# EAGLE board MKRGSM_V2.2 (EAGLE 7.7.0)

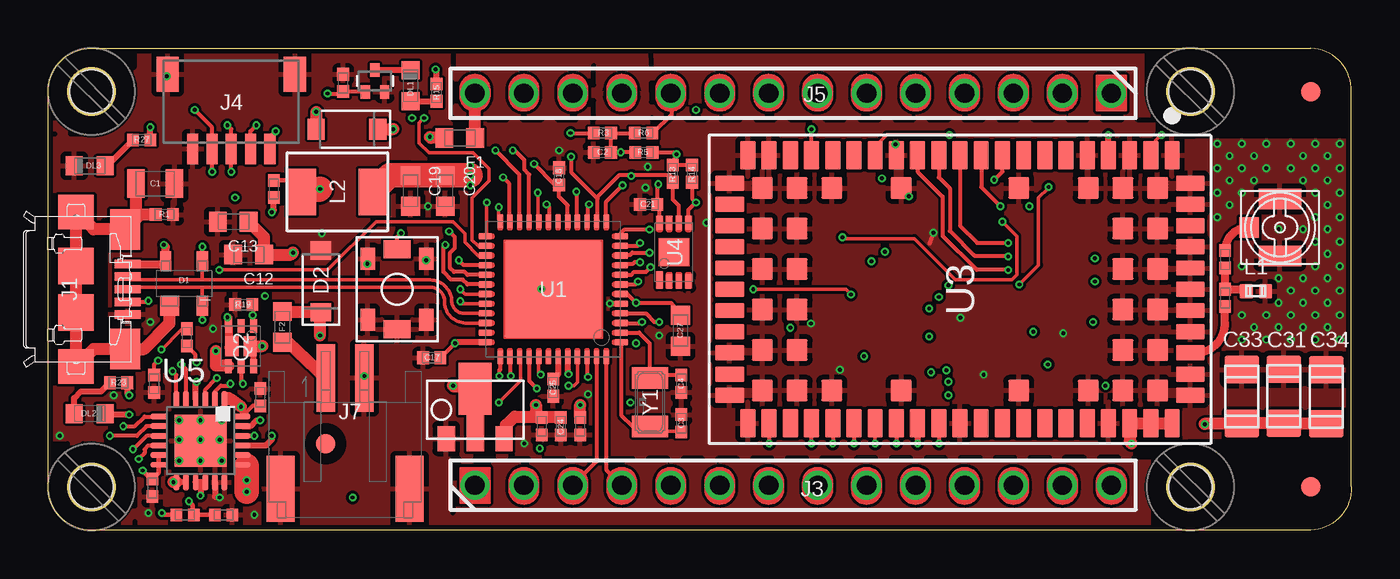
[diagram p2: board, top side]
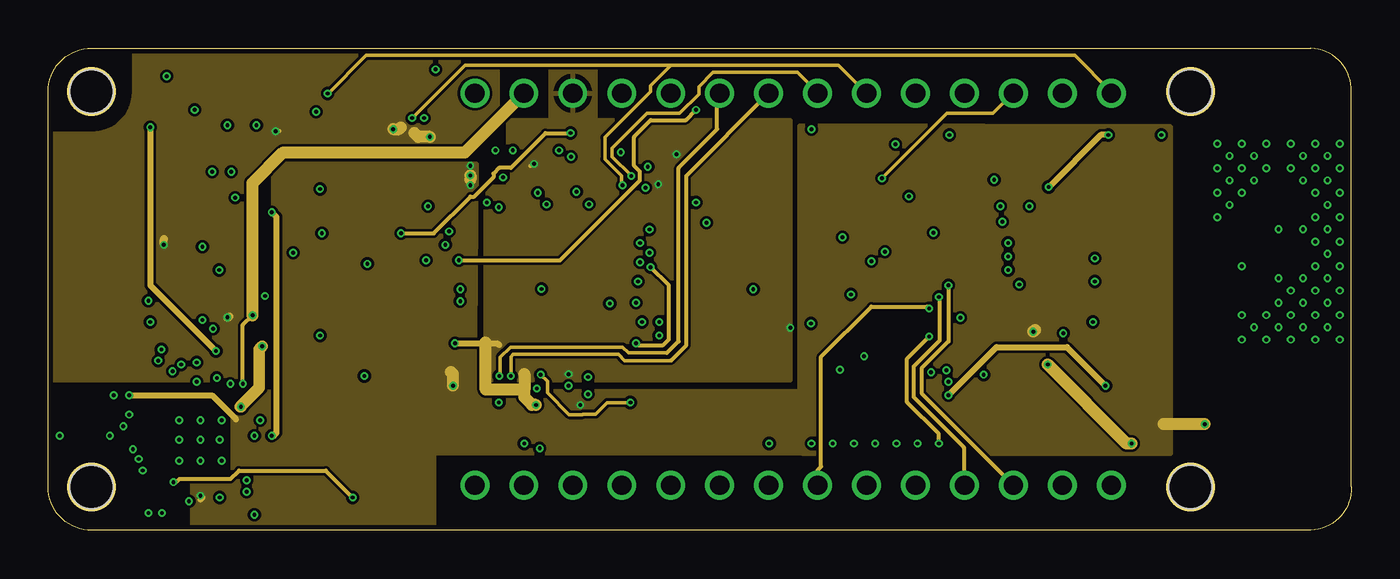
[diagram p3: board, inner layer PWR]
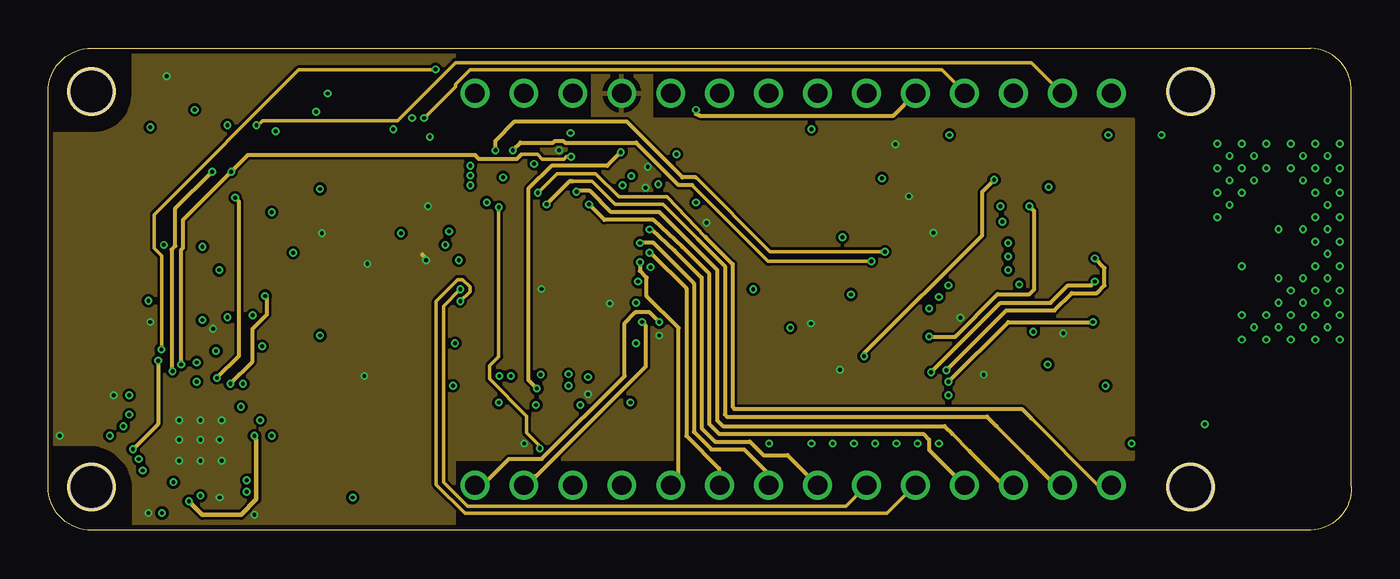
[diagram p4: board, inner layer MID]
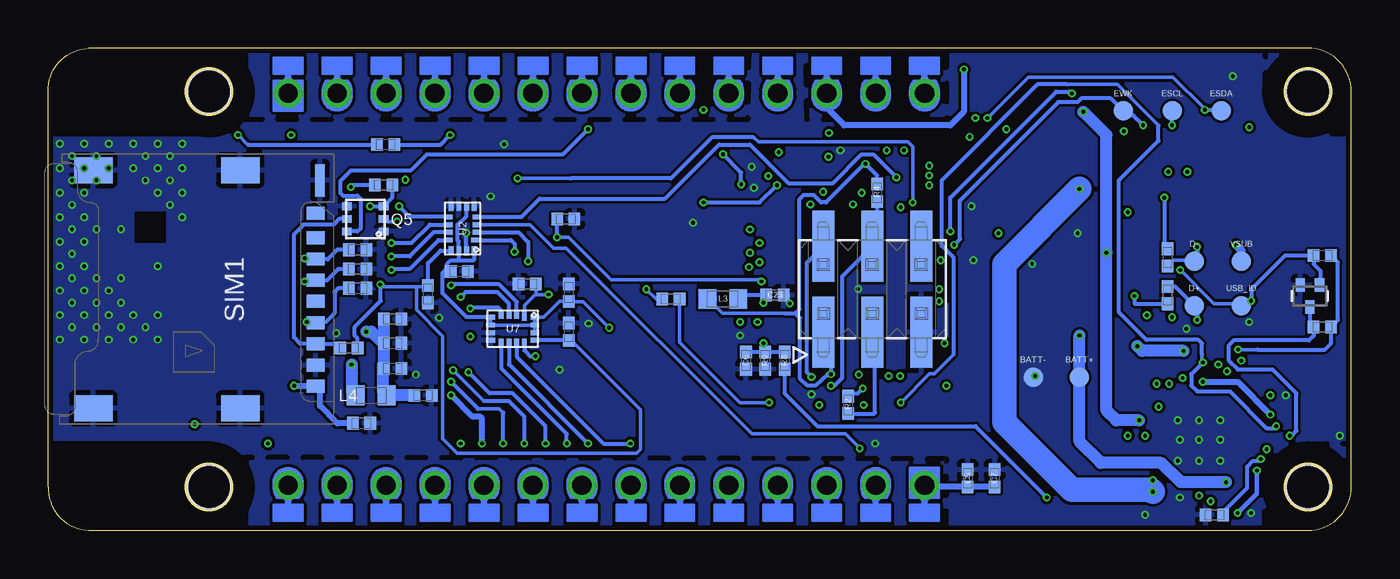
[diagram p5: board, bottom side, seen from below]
Size 67.6 x 25 mm. Coordinates in mm from the lower left corner, seen from the top.
Outline: 0,2.25 0,22.75 arc-90 2.25,25 65.5,25 arc-90 67.6,22.75 67.6,2.25 arc-90 65.5,0 2.25,0 arc-90 0,2.25
Copper layers (1*2*15*16): Top 0.035mm / dielectric 0.2mm / PWR 0.0175mm / dielectric 0.3mm / MID 0.0175mm / dielectric 0.2mm / Bottom 0.035mm
Design rules "B&B_4layers *": minimum track width 6mil, minimum drill 0.195mm, track to track 5.5mil, track to pad 5.5mil, pad to pad 5mil, via to via 5mil, smd to smd 0mil, copper to edge 10mil, drill to drill 8mil, minimum pad ring 6mil, minimum via ring 4mil, stop-mask expansion 4mil, vias tented up to drill 25mil, thermal gap 10mil
Net classes: 0 default: width 0.19 mm, drill 0.19 mm; 1 usb: width 0.19 mm, drill 0.19 mm, clearance 0.127 mm
Holes 2.25 mm at 2.25,2.25 59.25,2.25 59.25,22.75 2.25,22.75
tRestrict: area 0,0 to 4.5,4.5; area 0,20.5 to 4.5,25; area 57,20.5 to 61.5,25; area 57,0 to 61.5,4.5; 115 lines
bRestrict: area 0,0 to 4.5,4.5; area 0,20.5 to 4.5,25; area 57,0 to 61.5,4.5; area 57,20.5 to 61.5,25; 119 lines

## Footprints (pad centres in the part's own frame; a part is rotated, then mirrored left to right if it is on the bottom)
TP-1.00MM = smd 1 x 1 bottom: X 0,0
0805-R2013X50N@1 = smd 0.95 x 1.45: 1 -1,0; 2 1,0
0402-1005X55N = smd 0.62 x 0.62: 1 -0.45,0; 2 0.45,0
0603-1608X90N = smd 0.95 x 1: 1 -0.8,0; 2 0.8,0
C1206 = smd 1.8 x 1.45: 1 0,1.4; 2 0,-1.4
SOT190P230X110-4N = smd 1 x 1: 1 -1.15,0.75 | smd 1 x 0.6: 2 -1.15,-0.95; 3 1.15,-0.95; 4 1.15,0.95
SODFL3517X110N = smd 0.91 x 1.07: A 1.605,0; C -1.605,0
LEDC1608X80N-AK = smd 0.9 x 0.95: A 0.8,0; C -0.8,0
FD-1-1.5 = smd 1.016 x 1.016: P$1 0,0
ZX62-AB-5PA = smd 0.4 x 1.35: 1 -1.3,3.025; 2 -0.65,3.025; 3 0,3.025; 4 0.65,3.025; 5 1.3,3.025 | smd 2.1 x 1.6: 6 3.1,2.9; 11 -3.1,2.9 | smd 1.8 x 1.9: 7 4,0.35; 10 -4,0.35 | smd 1.9 x 1.9: 8 1.2,0.35; 9 -1.2,0.35
2X3_SMT = smd 1.143 x 3.683: 1 -2.54,-2.223; 2 -2.54,2.223; 3 0,-2.223; 4 0,2.223; 5 2.54,-2.223; 6 2.54,2.223
1X14_SMD_TH = drill 1: 1 0,0; 2 2.54,0; 3 5.08,0; 4 7.62,0; 5 10.16,0; 6 12.7,0; 7 15.24,0; 8 17.78,0; 9 20.32,0; 10 22.86,0; 11 25.4,0; 12 27.94,0; 13 30.48,0; 14 33.02,0
SM05B-SRSS-TB = smd 0.6 x 1.55: 1 -2,2.425; 2 -1,2.425; 3 0,2.425; 4 1,2.425; 5 2,2.425 | smd 1.2 x 1.8: SH1 -3.3,-1.45; SH2 3.3,-1.45
U.FL-R-SMT-1(60) = smd 1.05 x 2.2: GND1 -1.475,0; GND2 1.475,0 | smd 1.05 x 1: SIG 0,-1.6
JST-S2B-PH-SM4-TB = smd 1 x 3.5: 1 -1,2.95; 2 1,2.95 | smd 1.5 x 3.4: 3 3.35,-2.8; 4 -3.35,-2.8
C0402 = smd 0.75 x 0.7: 1 0,0.5; 2 0,-0.5
SRP4020 = smd 1.5 x 2.4: 1 -1.85,0; 2 1.85,0
C&K_PTS820_NO_HOLES = smd 1.15 x 0.75: 1 -1.575,1.525; 2 -1.575,-1.525; 3 1.575,1.525; 4 1.575,-1.525 | smd 0.95 x 1.4: 5 -2.075,0; 6 2.075,0
SOTFL50P160X78-3 = smd 0.5 x 0.66: D 0,0.57; G -0.5,-0.57; S 0.5,-0.57
SON65P205X205X75-8N-MWSD = smd 0.67 x 0.37: A 1.04,-0.65; D 1.04,0.65; G -1.04,0; K -1.04,-0.65; NC 1.04,0; S -1.04,0.65 | smd 1 x 0.7: D2 0,0.467; K2 0,-0.467
PWR_SC70-6L2 = smd 0.4 x 0.5: 1 -0.65,-0.95; 2 0,-0.95; 3 0.65,-0.95; 4 0.65,0.95; 5 0,0.95; 6 -0.65,0.95
MICROSIM8 = smd 0.67 x 0.95: CLK -0.47,6.77; GND 3.93,6.77; IO -1.57,6.77; NC1 -2.67,6.77; NC2 -3.94,6.77; RST 1.73,6.77; SW 2.83,6.77; VCC 5.03,6.77; VPP 0.63,6.77 | smd 1.7 x 0.5: SH1 -5.64,6.995 | smd 1.35 x 2: SH2 -6.175,2.865; SH3 6.175,2.865; SH4 -6.175,-4.755; SH5 6.175,-4.755
QFN50P700X700X90-49XN-EPSQ515 = smd 0.65 x 0.28: 1 -3.525,2.75; 2 -3.525,2.25; 3 -3.525,1.75; 4 -3.525,1.25; 5 -3.525,0.75; 6 -3.525,0.25; 7 -3.525,-0.25; 8 -3.525,-0.75; 9 -3.525,-1.25; 10 -3.525,-1.75; 11 -3.525,-2.25; 12 -3.525,-2.75; 25 3.525,-2.75; 26 3.525,-2.25; 27 3.525,-1.75; 28 3.525,-1.25; 29 3.525,-0.75; 30 3.525,-0.25; 31 3.525,0.25; 32 3.525,0.75; 33 3.525,1.25; 34 3.525,1.75; 35 3.525,2.25; 36 3.525,2.75 | smd 0.28 x 0.65: 13 -2.75,-3.525; 14 -2.25,-3.525; 15 -1.75,-3.525; 16 -1.25,-3.525; 17 -0.75,-3.525; 18 -0.25,-3.525; 19 0.25,-3.525; 20 0.75,-3.525; 21 1.25,-3.525; 22 1.75,-3.525; 23 2.25,-3.525; 24 2.75,-3.525; 37 2.75,3.525; 38 2.25,3.525; 39 1.75,3.525; 40 1.25,3.525; 41 0.75,3.525; 42 0.25,3.525; 43 -0.25,3.525; 44 -0.75,3.525; 45 -1.25,3.525; 46 -1.75,3.525; 47 -2.25,3.525; 48 -2.75,3.525 | smd 5 x 5: 49 0,0
RSV = smd 0.25 x 0.55: 1 -0.6,-0.7 | smd 0.25 x 0.45: 2 -0.2,-0.75; 3 0.2,-0.75; 4 0.6,-0.75; 9 0.6,0.75; 10 0.2,0.75; 11 -0.2,0.75; 12 -0.6,0.75 | smd 0.45 x 0.25: 5 1.15,-0.6; 6 1.15,-0.2; 7 1.15,0.2; 8 1.15,0.6; 13 -1.15,0.6; 14 -1.15,0.2; 15 -1.15,-0.2; 16 -1.15,-0.6
SARA-96 = smd 1.5 x 0.8: 1 -6.95,11; 2 -6.95,9.9; 3 -6.95,8.8; 4 -6.95,7.7; 5 -6.95,6.6; 6 -6.95,5.5; 7 -6.95,4.4; 8 -6.95,3.3; 9 -6.95,2.2; 10 -6.95,1.1; 11 -6.95,0; 12 -6.95,-1.1; 13 -6.95,-2.2; 14 -6.95,-3.3; 15 -6.95,-4.4; 16 -6.95,-5.5; 17 -6.95,-6.6; 18 -6.95,-7.7; 19 -6.95,-8.8; 20 -6.95,-9.9; 21 -6.95,-11; 33 6.95,-11; 34 6.95,-9.9; 35 6.95,-8.8; 36 6.95,-7.7; 37 6.95,-6.6; 38 6.95,-5.5; 39 6.95,-4.4; 40 6.95,-3.3; 41 6.95,-2.2; 42 6.95,-1.1; 43 6.95,0; 44 6.95,1.1; 45 6.95,2.2; 46 6.95,3.3; 47 6.95,4.4; 48 6.95,5.5; 49 6.95,6.6; 50 6.95,7.7; 51 6.95,8.8; 52 6.95,9.9; 53 6.95,11 | smd 0.8 x 1.5: 22 -5.5,-11.95; 23 -4.4,-11.95; 24 -3.3,-11.95; 25 -2.2,-11.95; 26 -1.1,-11.95; 27 0,-11.95; 28 1.1,-11.95; 29 2.2,-11.95; 30 3.3,-11.95; 31 4.4,-11.95; 32 5.5,-11.95; 54 5.5,11.95; 55 4.4,11.95; 56 3.3,11.95; 57 2.2,11.95; 58 1.1,11.95; 59 0,11.95; 60 -1.1,11.95; 61 -2.2,11.95; 62 -3.3,11.95; 63 -4.4,11.95; 64 -5.5,11.95 | smd 1.1 x 1.1: 65 -5.25,10.25; 66 -3.15,10.25; 67 -1.05,10.25; 68 1.05,10.25; 69 3.15,10.25; 70 5.25,10.25; 71 -5.25,8.45; 72 -3.15,8.45; 73 -1.05,8.45; 74 1.05,8.45; 75 3.15,8.45; 76 5.25,8.45; 77 -5.25,6.65; 78 5.25,6.65; 79 -5.25,3.05; 80 5.25,3.05; 81 -5.25,-3.05; 82 5.25,-3.05; 83 -5.25,-6.65; 84 5.25,-6.65; 85 -5.25,-8.45; 86 -3.15,-8.45; 87 -1.05,-8.45; 88 1.05,-8.45; 89 3.15,-8.45; 90 5.25,-8.45; 91 -5.25,-10.25; 92 -3.15,-10.25; 93 -1.05,-10.25; 94 1.05,-10.25; 95 3.15,-10.25; 96 5.25,-10.25
SON50P300X200X60-9N-EP160X140 = smd 0.85 x 0.3: 1 -1.45,0.75 | smd 0.7 x 0.3: 2 -1.525,0.25; 3 -1.525,-0.25; 4 -1.525,-0.75; 5 1.525,-0.75; 6 1.525,-0.25; 7 1.525,0.25; 8 1.525,0.75 | smd 1.4 x 1.6: 9 0,0
QFN24 = smd 0.3 x 0.85: 1 1.25,2.155; 2 0.75,2.155; 3 0.25,2.155; 4 -0.25,2.155; 5 -0.75,2.155; 6 -1.25,2.155; 13 -1.25,-2.155; 14 -0.75,-2.155; 15 -0.25,-2.155; 16 0.25,-2.155; 17 0.75,-2.155; 18 1.25,-2.155 | smd 0.85 x 0.3: 7 -2.155,1.25; 8 -2.155,0.75; 9 -2.155,0.25; 10 -2.155,-0.25; 11 -2.155,-0.75; 12 -2.155,-1.25; 19 2.155,-1.25; 20 2.155,-0.75; 21 2.155,-0.25; 22 2.155,0.25; 23 2.155,0.75; 24 2.155,1.25 | smd 2.7 x 2.7: 25 0,0
SOT89-3L = smd 0.9 x 1.3: 1 -1.5,0; 3 1.5,0 | smd 0.9 x 1.9: 2 0,0.3 | smd 1.7 x 2.7: TH 0,2.6
ABS07 = smd 1.1 x 1.9: 1 -1.25,0; 2 1.25,0

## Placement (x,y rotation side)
BATT+  DNP  [TP-1.00MM]  14.1,7.95 0 top
BATT-  DNP  [TP-1.00MM]  16.5,7.95 0 top
C1  4n7  [0805-R2013X50N@1]  5.55,17.98 0 top
C2  100n  [0402-1005X55N]  28.75,19.6 180 top
C3  20p  [0402-1005X55N]  32.85,5.55 270 top
C4  20p  [0402-1005X55N]  32.85,7.6 90 top
C5  4u7  [0402-1005X55N]  19.9,2.7 90 bottom
C6  100n  [0402-1005X55N]  31.4,8.8 270 bottom
C7  100n  [0402-1005X55N]  18.5,2.7 90 bottom
C8  100n  [0402-1005X55N]  46.27,13.43 180 bottom
C9  100n  [0402-1005X55N]  47.9,12.25 270 bottom
C10  15p  [0402-1005X55N]  61.05,12.05 90 top
C11  33p  [0402-1005X55N]  61.05,14.05 90 top
C12  10u  [0603-1608X90N]  10.4,14.3 180 top
C13  10u  [0603-1608X90N]  9.6,16 180 top
C14  1u  [0402-1005X55N]  11,6.9 90 top
C15  47n  [0402-1005X55N]  11.7,17.7 90 top
C16  4u7  [0402-1005X55N]  9.1,0.8 0 top
C17  100n  [0402-1005X55N]  19.9,8.95 180 top
C18  100n  [0402-1005X55N]  26.5,18.35 90 top
C19  10u  [0603-1608X90N]  18.8,17.6 270 top
C20  10u  [0603-1608X90N]  20.6,17.6 270 top
C21  100n  [0402-1005X55N]  31.15,16.9 180 top
C22  1u  [0402-1005X55N]  27.6,5.4 270 top
C23  100n  [0402-1005X55N]  29.9,12.2 0 bottom
C24  100n  [0402-1005X55N]  26.6,5.4 270 top
C25  1u  [0402-1005X55N]  26.2,7.4 270 top
C26  1u  [0402-1005X55N]  25.6,5.4 270 top
C27  4u7  [0603-1608X90N]  32.8,10.35 270 top
C28  10n  [0402-1005X55N]  48.15,7 0 bottom
C29  100n  [0402-1005X55N]  49.74,8.39 0 bottom
C30  15p  [0402-1005X55N]  49.74,9.7 0 bottom
C31  100uF  [C1206]  64.1,6.95 180 top
C32  100n  [0402-1005X55N]  51.35,5.55 180 bottom
C33  100uF  [C1206]  61.91,6.94 180 top
C34  100uF  [C1206]  66.3,6.92 180 top
C35  100n  [0402-1005X55N]  40.6,12.32 270 bottom
C36  100n  [0402-1005X55N]  40.6,10.3 90 bottom
C37  56p  [0402-1005X55N]  49.74,10.95 0 bottom
D1  PRTR5V  [SOT190P230X110-4N]  7.05,12.8 90 top
D2  PMEG6020  [SODFL3517X110N]  14.15,12.9 90 top
D3  PMEG6020  [SODFL3517X110N]  15.5,20.8 180 top
D4  PESD0402  [0402-1005X55N]  51.55,12.55 180 bottom
D5  PESD0402  [0402-1005X55N]  51.55,13.55 180 bottom
D6  PESD0402  [0402-1005X55N]  51.55,14.55 180 bottom
D+  DNP  [TP-1.00MM]  8.15,11.65 0 top
D-  DNP  [TP-1.00MM]  8.15,13.95 0 top
DL1  YELLOW  [LEDC1608X80N-AK]  18.8,23.05 270 top
DL2  ORANGE  [LEDC1608X80N-AK]  2.15,6.05 180 top
DL3  GREEN  [LEDC1608X80N-AK]  2.15,18.9 0 top
ESCL  DNP  [TP-1.00MM]  9.29,21.75 0 top
ESDA  DNP  [TP-1.00MM]  6.75,21.75 0 top
EWK  DNP  [TP-1.00MM]  11.83,21.75 0 top
F1  MFFSMF050  [0603-1608X90N]  21.35,20.35 180 top
F2  MFFSMF050  [0603-1608X90N]  12.15,10.55 90 top
FD1  DNP  [FD-1-1.5]  14.4,4.5 0 top
FD2  DNP  [FD-1-1.5]  65.5,22.75 0 top
FD3  DNP  [FD-1-1.5]  65.5,2.25 0 top
FRAME1  DNP  [FRAME]  not placed on the board
FRAME2  DNP  [FRAME-NO-BAN]  not placed on the board
J1  -  [ZX62-AB-5PA]  1.1,12.5 270 top
J2  DNP  [2X3_SMT]  24.85,12.5 0 bottom
J3  -  [1X14_SMD_TH]  22.13,2.34 0 top
J4  -  [SM05B-SRSS-TB]  9.5,22.2 180 top
J5  -  [1X14_SMD_TH]  55.15,22.66 180 top
J6  -  [U.FL-R-SMT-1(60)]  63.9,15.7 270 top
J7  -  [JST-S2B-PH-SM4-TB]  15.4,4.95 0 top
L1  39nH  [C0402]  62.65,12.4 270 top
L2  2u2  [SRP4020]  15,17.55 0 top
L3  BLM18PG471  [0603-1608X90N]  32.6,12 0 bottom
L4  BLM18EG221  [0603-1608X90N]  50.85,7 180 bottom
PB1  PTS820  [C&K_PTS820_NO_HOLES]  18.1,12.5 90 top
Q1  2N7002  [SOTFL50P160X78-3]  16.95,23.3 0 top
Q2  SIA817  [SON65P205X205X75-8N-MWSD]  10,9.55 90 top
Q3  2N7002  [SOTFL50P160X78-3]  2.15,12.15 180 bottom
Q5  2N7002DW-7-FNO_PAD  [PWR_SC70-6L2]  51.15,16.15 90 bottom
R1  1M  [0402-1005X55N]  6.03,16.38 180 top
R2  39R  [0402-1005X55N]  26.1,6.5 90 bottom
R3  330R  [0402-1005X55N]  28.75,20.6 0 top
R4  1k  [0402-1005X55N]  24.6,17.5 90 bottom
R5  10k  [0402-1005X55N]  30.9,19.6 0 top
R6  330R  [0402-1005X55N]  30.89,20.6 0 top
R7  DNP  [0402-1005X55N]  9.53,12.2 270 bottom
R8  330k  [0402-1005X55N]  29.4,8.8 270 bottom
R9  1M2  [0402-1005X55N]  30.4,8.8 90 bottom
R10  100k  [0402-1005X55N]  40.75,16.15 180 bottom
R11  0R  [0402-1005X55N]  35.3,12 0 bottom
R12  100k  [0402-1005X55N]  50.1,20 180 bottom
R13  4k7  [0402-1005X55N]  32.4,18.5 90 top
R14  4k7  [0402-1005X55N]  33.4,18.5 90 top
R15  330R  [0402-1005X55N]  20.15,22.7 270 top
R16  100k  [0402-1005X55N]  15.3,23.2 270 top
R17  DNP  [0402-1005X55N]  9.53,14.15 90 bottom
R18  DNP  [0402-1005X55N]  42.75,12.78 0 bottom
R19  100k  [0402-1005X55N]  10.15,11.7 0 top
R21  10k  [0402-1005X55N]  1.5,14.25 180 bottom
R23  330R  [0402-1005X55N]  3.65,7.65 0 top
R24  10k  [0402-1005X55N]  7.2,10 270 top
R25  10k  [0402-1005X55N]  5.5,7.6 90 top
R26  10k  [0402-1005X55N]  1.5,10.55 180 bottom
R27  390R  [0402-1005X55N]  4.85,20.25 0 top
R28  330R  [0402-1005X55N]  7.1,0.8 180 bottom
R29  10k  [0402-1005X55N]  5.4,2.2 90 top
R30  5k49  [0402-1005X55N]  7.1,0.8 180 top
R31  10k  [0402-1005X55N]  52,9.45 0 bottom
R32  1k  [0402-1005X55N]  50.2,17.9 180 bottom
SIM1  -  [MICROSIM8]  60.5,12.5 270 bottom
U1  D21G18  [QFN50P700X700X90-49XN-EPSQ515]  26.2,12.5 180 top
U2  SN74AVC4T774  [RSV]  46.1,15.65 90 bottom
U3  SARA-U201  [SARA-96]  47.3,12.5 270 top
U4  ECC508  [SON50P300X200X60-9N-EP160X140]  32.46,14.43 90 top
U5  BQ24195L  [QFN24]  7.9,4.65 0 top
U6  AP721533  [SOT89-3L]  22.15,4.75 0 top
U7  SN74AVC4T774  [RSV]  43.5,10.45 180 bottom
U$5  [MH_RND_F_2.2MM_NM]  2.25,2.25 90 top
U$6  [MH_RND_F_2.2MM_NM]  2.25,22.75 90 top
U$7  [MH_RND_F_2.2MM_NM]  59.25,22.75 90 top
U$8  [MH_RND_F_2.2MM_NM]  59.25,2.25 90 top
USB_ID  DNP  [TP-1.00MM]  5.7,11.65 0 top
VSUB  DNP  [TP-1.00MM]  5.7,13.95 0 top
Y1  32768Hz  [ABS07]  31.23,6.64 270 top

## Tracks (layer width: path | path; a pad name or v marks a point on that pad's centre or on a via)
+1V8  (via drill 0.2)
  Top 0.19: v50.38,12.75 51.38,13.75 51.38,17.25 51.88,17.75 v51.9,17.8
  Top 0.305: U3.4 v55,20.5
  PWR 0.305: v55,20.5 54.6,20.5 v51.9,17.8
  Bottom 0.19: 48.5,12.62 48.5,11.43 47.15,10.07 47.15,4.75 46.4,4 37.08,4 36.88,4.2 36.88,6.25 40.38,9.75 C36.1 | 48.5,12.62 48,12.62 C9.1 | v50.38,12.75 50.25,12.62 48.5,12.62
  Bottom 0.2: C36.1 U7.13 | C9.1 47.9,13.85 47.25,14.5 U2.13 | R32.2 51.8,17.9 v51.9,17.8 | R31.2 51.55,9.95 51.7,10.1 51.7,10.55 50.35,11.9 50.35,12.72 v50.38,12.75
+3V3  (via drill 0.2)
  Top 0.19: v5.88,9.38 6.88,10.38 7.12,10.38 R24.1
  Top 0.2: R14.2 R13.2 v32.6,19.5 32.5,19.6 R5.2 | U4.8 31.71,16.74 C21.1 31.6,17.9 v31.65,17.95 | U1.17 26.95,16.85 26.5,17.3 C18.1 26.3,17.9 v25.2,19 | C17.1 v21.1,9.7
  Top 0.305: U1.44 26.95,8.15 v27,8.1 | U1.36 21.15,9.75 v21.1,9.7 | R15.1 20.15,23.85 v20.1,23.9
  Top 0.61: U6.3 23.75,5.45 24.2,5.9 25.1,5.9 | 25.1,5.9 25.55,5.9 C26.1 C24.1 | v25.3,6.5 25.3,6.1 25.1,5.9
  PWR 0.2: v25.2,19 25.1,19 25,18.9
  PWR 0.305: v21.1,9.7 23.3,9.7 23.4,9.6
  PWR 0.61: v25.3,6.5 25.1,6.5 24.7,6.9 24.7,7.3 | 24.7,8.1 24.7,7.3 | 24.7,7.3 22.7,7.3 22.7,9.62 U1.36
  MID 0.19: v5.88,9.38 5.88,14.25 5.5,14.62 5.5,16.38 13,23.88 20,23.88 v20.1,23.9
  Bottom 0.19: v5.88,9.38 4.88,9.38 | 29.38,11.25 32.62,11.25 33.38,12 L3.1 | 25.25,19 v25.2,19 | 32.62,19.5 v32.6,19.5 | U7.6 44.62,10.62 42.38,10.62 U7.15 | v38.5,10.5 39.85,11.85 40.38,11.85 C35.2 41.08,11.88 41.9,11.05 42.3,11.05
  Bottom 0.2: 25.25,19 27.25,17 27.5,17 27.9,17.4 28.4,17.4 28.62,17.18 28.62,11.47 28.85,11.25 | v31.65,17.95 31.65,18.55 v32.6,19.5 | 29.38,11.25 28.85,11.25 | 28.85,11.25 28.6,11 28.6,7.85 28.2,7.5 27.8,7.5 27.15,8.1 v27,8.1 27,9.89 | R26.1 1.05,10.75 | R21.1 0.7,13.9 0.7,10.9 R26.1 | 4.88,9.38 1.38,9.38 1.05,9.7 R26.1 | U7.14 U7.15 U7.16 42.3,11.05 | U7.6 U7.5 45.9,11.05 47.15,12.3 47.15,13.35 46.9,13.6 | 46.9,13.6 C8.2 | 45.88,16.77 U2.6 45.9,16.27 46.38,15.85 46.38,15.05 46.3,14.97 U2.14 46.3,14.05 46.25,14 | R4.2 24.6,18.4 v25.2,19 | U2.16 45.5,14.05 45.55,14 46.25,14 | 46.9,13.6 46.9,13.82 46.73,14 46.25,14
  Bottom 0.305: 27,9.89 J2.1 | v20.1,23.9 20.1,21.7 20.8,21 26.3,21 27.2,21.9 27.2,22.64 J5.12
  pour PWR: 26.05,25 26.05,21.25 23.85,21.25 23.85,17.85 23.8,17.8 22.7,17.8 22.7,7.8 38.5,7.8 38.5,21.25 28.4,21.25 28.4,24.95
+3V8  (via drill 0.2)
  Top 0.305: U5.15 U5.16 8.1,2.5 7.9,2.3 v7.9,1.8 | R23.2 4.1,7.1 v4.2,7
  Top 0.61: C34.1 64.12,5.53 C31.1 61.92,5.55 C33.1 60.04,5.54 v60,5.5 | U6.2 U6.TH 21.05,7.45 v21,7.5 | C22.1 v27.6,6.5
  Top 1.27: L2.2 17.7,18.4 C19.1 C20.1 v21.9,18.4
  PWR 0.305: v7.9,1.8 7.9,1.6 8,1.7 | v4.2,7 8.5,7 9.75,5.75
  PWR 0.61: v60,5.5 57.85,5.5 | 51.2,10.4 v51.1,10.3 | v21.9,18.4 21.9,18.2 | v21,7.5 21,8.1 20.9,8.2
  Bottom 0.61: C28.1 L4.1 50.25,7.2 50.25,8.57 C29.1 C30.1 | v51.1,10.3 50.84,10.3 C30.1 | C37.1 C30.1
  other vias: 21.9,18.9 21.9,17.9
  pour PWR: 9.6,7.2 11.7,7.2 11.7,19 22.2,19 22.1,7.2 39,7.2 39,21 58.2,20.95 58.2,3.95 20,4 20,0 7.5,0 7.5,2.9 9.6,2.9
+5V  (via drill 0.2)
  Top 0.2: J4.1 11.5,20.4 v11.8,20.7
  Top 0.406: J1.1 5.95,13.8 D1.4 6.1,14.7 v6,14.8 | Q2.D2 9.35,9.48 Q2.D 9.35,11 v9.3,11.05
  Top 0.61: F1.2 19.85,20.35 v19.8,20.4 | D3.C v17.9,20.8
  PWR 0.2: v11.8,20.7 12,20.7
  PWR 0.406: v6,14.8 6,15.1 | v9.3,11.05 9.3,11 9.4,11.1
  PWR 0.61: v19.8,20.4 19.2,20.4 19,20.6 | v17.9,20.8 18.2,20.8 18.3,20.9
  Bottom 0.406: VSUB.X 5.7,14.5 v6,14.8
  pour PWR: 23.3,25 4.45,25 4.45,22.7 arc-90 2.3,20.55 0,20.55 0,7.8 11.2,7.8 11.2,19.5 23.3,19.5
GND  (via drill 0.2)
  Top 0.19: 55.62,7.5 U3.76 | 55.5,9 55.62,9
  Top 0.2: PB1.4 19.62,14.03 v19.6,14 | v45.92,15.43 45.73,14.88
  Top 0.305: U5.17 8.65,1.75 v8.9,1.7
  MID 0.2: v19.6,14 19.6,14.1 19.4,14.3
  Bottom 0.2: C23.2 29.45,12.08 v29.14,11.77 | 45.9,15.4 v45.92,15.43 45.92,14.57 45.9,14.57 U2.15
  other vias: 31.7,10.1 6.8,5.7 7.9,5.7 9,5.7 9,3.6 7.9,3.6 6.8,3.6 6.8,4.7 7.9,4.7 8.9,4.7 5.3,10.8 5.2,0.9 10.7,0.8 24.7,4.5 28,7.05 26.5,19.7 8.55,10.45 3.4,7 67,20.05 65.73,20.05 64.46,20.05 61.92,20.05 63.19,20.05 60.65,20.05 60.65,18.78 60.65,17.51 60.65,16.24 61.92,17.51 61.92,18.78 63.19,18.78 64.46,18.78 65.73,18.78 67,18.78 67,17.51 65.73,17.51 67,16.24 67,14.97 67,13.7 67,12.43 67,11.16 65.73,11.16 64.46,11.16 61.92,11.16 63.19,11.16 61.92,9.89 63.19,9.89 64.46,9.89 65.73,9.89 67,9.89 65.73,12.43 64.46,12.43 65.73,13.7 65.73,14.97 65.73,16.24 61.92,13.7 62.55,10.53 63.83,10.53 65.09,10.53 66.36,10.53 66.36,11.79 65.09,11.79 63.83,11.79 66.36,13.06 65.09,13.06 66.36,14.34 66.36,15.61 66.36,16.88 65.09,15.61 63.83,15.61 66.36,18.14 65.09,18.14 62.55,18.14 61.28,18.14 61.28,19.41 62.55,19.41 61.28,16.88 63.83,13.06 66.36,19.41 65.09,19.41 14.2,15.4 43.95,20.02 44.66,17.32 16.55,13.81 19.7,16.8 25.59,12.52 16.4,8 30.98,17.77 34.15,15.95 31.1,18.85 0.6,4.9 6.15,23.55 48.52,8.07 47.33,11.03 39.58,10.72 41.08,8.32 52.66,10.21
  pour Bottom: 0,0 0,25 67.6,25 67.6,0
  pour Top: 0,-0.1 0,24.9 28.5,25 57.3,25.1 57.3,0.1
  pour Top (isolate 0.1): 57.3,25.1 67.6,25.1 67.6,0 57.3,0
  pour MID: 0,20.55 2.4,20.55 arc90 4.45,22.6 4.45,25 21,25 21,21.3 28.3,21.3 28.3,25 31.25,25 31.25,21.3 56.25,21.3 56.25,3.7 21,3.7 21,0 4.5,0 4.5,2.1 arc90 2.1,4.5 0,4.5
MCTS  (via drill 0.2)
  Top 0.2: U3.11 47.3,15.8 48.2,14.9 v49.8,14.9
  Bottom 0.2: v49.8,14.9 48.75,14.9 47.8,15.85 U2.10
MDTR  (via drill 0.2)
  Top 0.2: v49.08,18.18 49.5,18.6 U3.9
  MID 0.2: v42.33,9.03 42.33,9.18 48.45,15.3 48.45,17.55 v49.08,18.18
  Bottom 0.2: U7.12 42.9,9.32 42.6,9.03 v42.33,9.03
MI2SCLK  (via drill 0.2)
  Top 0.2: v39.6,4.5 U3.36
  Bottom 0.19: v39.6,4.5 39.7,4.5
  Bottom 0.2: v39.6,4.5 43.7,8.6 U7.10
MI2SFS  (via drill 0.2)
  Top 0.2: U3.34 v37.4,4.5
  Bottom 0.2: v37.4,4.5 38.8,4.5 43.3,9 U7.11
MI2SRX  (via drill 0.2)
  Top 0.2: U3.37 v40.7,4.5
  Bottom 0.2: v40.7,4.5 40.7,5 44.1,8.4 U7.9
MRST  (via drill 0.2)
  Top 0.2: U3.18 v39.6,20.8
  Bottom 0.2: v39.6,20.8 40.9,19.5 47.95,19.5 48.8,18.65 51.9,18.65 52.45,18.1 52.45,17.5 52.3,17.35 51.55,17.35 51.4,17.2 51.4,15.65 51.55,15.5 Q5.6
MRTS  (via drill 0.2)
  Top 0.2: U3.10 48.4,17.8 v49.4,16.8
  Bottom 0.2: U2.9 48.85,16.25 v49.4,16.8
MRX  (via drill 0.2)
  Top 0.2: U3.13 45.1,18.6 46.4,17.3 46.4,15.28 48.17,13.5 v49.8,13.5
  Bottom 0.2: v49.8,13.5 49.73,13.57 48.83,13.57 47.35,15.05 U2.12
MTX  (via drill 0.2)
  Top 0.2: U3.12 46.2,18.3 46.77,17.73 46.77,15.53 48.05,14.25 49.75,14.25 v49.8,14.2
  Bottom 0.2: U2.11 47.6,15.45 48.85,14.2 v49.8,14.2
N17658775  (via drill 0.2)
  Top 0.2: PB1.6 18.1,15.2 v18.3,15.4 | v27.1,20.6 R3.1
  PWR 0.2: v27.1,20.6 25.8,20.6 24,18.8 23.4,18.8 23.1,18.5 23.1,18.3 22.1,17.3 21.9,17.3 20,15.4 v18.3,15.4
N17798864
  Top 0.305: DL2.A 1.35,6.85 1.7,7.2 2.75,7.2 R23.1
N17834267
  Top 0.305: DL3.A 3.05,18.9 R27.1
N17852357  (via drill 0.2)
  Top 0.2: U1.6 30.05,12.25 v30.5,11.8 32.3,11.8 C27.1
  Bottom 0.2: v30.5,11.8 30.45,12.1 C23.1 31.6,12.2 L3.2
N17852431
  Top 0.305: U1.43 26.45,8.1 C25.1
N$1
  Top 0.61: R1.2 4.78,16.38 | 4.78,16.38 J1.11 2.35,15.6 J1.10 J1.9 J1.8 J1.7 2.35,9.4 J1.6 4.97,9.4 6.3,10.72 D1.1 | C1.1 4.55,16.6 4.78,16.38
N$2
  Top 0.61: F1.1 22.15,22.64 J5.14
N$3
  Top 0.61: F2.1 12.45,9.75 J7.1
N$4
  Bottom 0.2: J2.3 24.7,10.13 24.7,6.1 24.75,6.05 R2.1
N$5
  Top 0.406: U3.56 59.5,9.2 arc90 61.05,10.75 C10.1
N$6  (via drill 0.2)
  Top 0.2: U1.8 30.25,13.25 30.4,13.4 31,13.4 v31.25,13.65
  PWR 0.2: v30.5,9.7 30.6,9.6 31.9,9.6 32.2,9.9 32.2,12.7 v31.25,13.65
  Bottom 0.2: C6.1 R9.2 | R9.2 R8.1 | R9.2 30.4,9.6 v30.5,9.7
N$7
  Top 0.305: DL1.A R15.2
N$8
  Top 0.406: J6.SIG 62.25,15.7 arc90 C11.2
N$9  (via drill 0.2)
  Top 0.19: v36.58,12.5 41.38,12.5 v41.65,12.22
  Bottom 0.19: R18.2 42.3,12.28 42.35,12.22 | 42.35,12.22 42.9,11.68 U7.1 | v41.65,12.22 42.35,12.22 | R11.1 36.08,12 v36.58,12.5
N$10
  Top 0.305: DL1.C 16.97,23.85 Q1.D
N$11  (via drill 0.2)
  Top 0.2: U3.42 v46.2,4.5
  PWR 0.2: v46.2,4.5 46.2,5 44.55,6.65 44.55,8.9 v45.7,10.05
  MID 0.2: v45.7,10.05 47.05,10.05 49.25,12.25 50.9,12.25 51.15,12.5 51.15,16.55 v50.9,16.8
  Bottom 0.2: R32.1 49.75,17.25 Q5.3 v50.9,16.8
N$12  (via drill 0.2)
  Top 0.61: U3.53 U3.52 U3.51 56.1,4.6 v56.2,4.5
  PWR 0.61: v56.2,4.5 55.95,4.5 v51.85,8.6
  Bottom 0.61: v51.85,8.6 51.85,7.2 L4.2
N$13  (via drill 0.2)
  Top 0.19: v46.75,20.5 43.5,20.5 43,20 43,19.5 U3.15
  Bottom 0.2: R12.1 47.25,20 v46.75,20.5
N$14
  Top 0.406: C11.1 C10.2 62.05,12.5 arc-90 L1.2
N$15  (via drill 0.2)
  Top 0.24: C15.2 13.15,18.15 L2.1
  Top 0.305: v10.3,2.6 10.3,3.35 10.24,3.4 U5.19 U5.20
  Top 1.27: L2.1 14.05,17.65 v14.1,17.7 | v10.3,2 10.3,3.35
  Bottom 1.27: v10.3,2 10.4,2.1 14.5,2.1 18,5.6 18,13.8 v14.1,17.7
N$16  (via drill 0.2)
  Top 0.2: U5.2 8.65,7.2 8.95,7.5 9.35,7.5 v9.45,7.6
  MID 0.2: v9.45,7.6 10.6,8.75 10.6,10.45 11.35,11.2 11.35,12.05 v11.25,12.15
  Bottom 0.2: v11.25,12.15 11.25,11.75 R7.2
N$17  (via drill 0.2)
  Top 0.19: 10.1,6.2 v10,6.4
  Top 0.2: 10.1,6.1 10.1,5.95 U5.24 10.61,6.45 C14.1 | U5.1 9.39,6.8
  Top 0.305: Q2.K 10.65,9.12 Q2.K2 | R27.2 v5.3,20.9 | 10.1,6.1 10.1,6.2
  Top 0.605: 9.39,6.8 9.49,6.8 v10,6.4
  Top 0.61: 9.35,6.85 9.39,6.8 9.4,6.8 | Q2.K2 v11.1,9.55 | v8.7,9.3 8.7,8.55 9.31,8.55 Q2.S
  PWR 0.305: v5.3,20.9 5.3,12.7 v8.7,9.3
  PWR 0.605: v10,6.4 9.95,6.4 10.95,7.4 10.95,9.4 v11.1,9.55
  Bottom 0.61: v8.7,9.3 10.85,9.3 v11.1,9.55
N$18  (via drill 0.2)
  Top 0.305: U5.21 11.3,4.4 11.6,4.7 v11.6,4.9 | v11.6,16.5 11.7,16.6 C15.1
  PWR 0.305: v11.6,4.9 11.7,4.9 11.85,5.05 11.85,16.25 v11.6,16.5
N$19  (via drill 0.2)
  Top 0.2: U5.10 5.2,4.4 5,4.2 5,4 v4.7,3.7
  Bottom 0.2: R28.1 6.65,0.95 5.4,2.2 5.4,3.3 5.1,3.6 4.8,3.6 v4.7,3.7
N$20  (via drill 0.2)
  Top 0.2: U5.3 8.15,7.3 v8.75,7.9
  MID 0.2: v8.75,7.9 9.9,9.05 9.9,17.05 v9.7,17.25
  Bottom 0.2: R17.2 9.7,14.82 v9.7,17.25
N$21  (via drill 0.2)
  Top 0.24: C16.1 R30.1 7.5,0.85 7.5,1.3 v7.3,1.5 | U5.22 v10.7,4.9
  MID 0.24: v10.7,4.9 10.7,4.8 10.8,4.7 10.8,1.6 10,0.8 8,0.8 v7.3,1.5
N$22  (via drill 0.2)
  Top 0.2: U5.8 5.1,5.4 4.6,4.9 v3.2,4.9
  Bottom 0.2: v3.2,4.9 3.1,4.9 2.85,5.15 2.85,7.1 4.1,8.35 5.9,8.35 6.35,8.8 6.35,9.6 6.1,9.85 2.2,9.85 1.95,10.1 R26.2 2.15,10.75 Q3.D
N$23  (via drill 0.2)
  Top 0.24: U5.11 U5.12 5.75,3 R29.2 5.35,2.65 v4.9,3.1 | R30.2 6,0.8 v5.9,0.9
  Bottom 0.24: v4.9,3.1 4.9,1.9 v5.9,0.9
N$24  (via drill 0.2)
  Top 0.2: R25.2 5.5,8.6 v5.7,8.8 | U5.9 5.1,4.9 v4.4,4.2
  MID 0.2: v5.7,8.8 5.7,5.5 v4.4,4.2
PA00_XIN32
  Top 0.2: U1.1 29.73,5.97 30.3,5.4 31.21,5.4 Y1.2 31.46,5.15 C3.2
PA01_XOUT32
  Top 0.2: U1.2 30.65,10.25 31.2,9.7 31.2,8.61 Y1.1 31.39,8.05 C4.2
PA02_AIN0  (via drill 0.2)
  Top 0.2: U1.3 30.75,10.75 v30.8,10.8
  MID 0.2: J3.2 25.14,2.8 25.3,2.8 31,8.5 31,10.6 v30.8,10.8
PA03_VREFA  (via drill 0.2)
  Top 0.2: U1.4 31,11.25 31.45,10.8 v31.7,10.8
  MID 0.2: v31.7,10.8 31.2,11.3 30.45,11.3 29.9,10.75 29.9,8 25.6,3.7 23.9,3.7 22.61,2.4 22.2,2.4 J3.1
  Bottom 0.305: C7.1 C5.1 22.05,2.25 J3.1
PA04_AIN4  (via drill 0.2)
  Top 0.2: v30.7,13.9 30.4,13.9 30.3,13.8 29.77,13.8 U1.9
  MID 0.2: J3.5 32.3,2.4 32.7,2.8 32.7,10.5 31.05,12.15 31.05,13.1 30.7,13.45 v30.7,13.9
PA05_AIN5  (via drill 0.2)
  Top 0.2: U1.10 29.77,14.3 30.2,14.3 30.3,14.4 v31.2,14.4
  MID 0.2: J3.6 34.8,2.38 34.8,3.2 33.1,4.9 33.1,12.55 31.3,14.35 31.3,14.4 v31.2,14.4
PA06_AIN6  (via drill 0.2)
  Top 0.2: U1.11 30.55,14.75 v30.7,14.9
  MID 0.2: v30.7,14.9 31.4,14.9 33.5,12.8 33.5,5.1 34.4,4.2 36.1,4.2 37.4,2.9 37.4,2.37 J3.7
PA07_AIN7  (via drill 0.2)
  Top 0.2: U1.12 29.73,15.43 29.9,15.6 v31.2,15.6
  PWR 0.2: J3.8 39.91,3.12 40.1,3.3 40.1,9 42.7,11.6 45.6,11.6 v45.7,11.5
  MID 0.2: v31.2,15.6 31.3,15.6 32.5,14.5 33.9,13.1 33.9,5.3 34.6,4.6 36.4,4.6 37.1,3.9 38.35,3.9 J3.8
  Bottom 0.2: 45.62,11.57 v45.7,11.5 45.65,11.55 44.25,11.55 44.1,11.4 U7.4
PA08_S0_I2C_SDA  (via drill 0.2)
  Top 0.2: U1.13 28.95,17.05 v29.8,17.9 | 33.61,16.99 v33.6,17 | v7.6,21.8 8.5,20.9 J4.4 v8.5,18.6 | U5.6 6.65,8.05 v6.45,8.25 | U4.5 33.21,16.61 v33.6,17 | R14.1 33.4,17.2 v33.6,17
  PWR 0.19: 32.26,24.06 32.33,24.12 41,24.12 42.38,22.75 J5.6 | 32.26,24.06 31.25,23.05 31.25,22.75 28.88,20.38 28.88,19.25 29.75,18.38 29.75,18 v29.8,17.9 | v18.88,21.38 21.62,24.12 32.25,24.12 32.26,24.06
  MID 0.2: v6.45,8.25 6.4,8.3 6.4,14.55 6.6,14.75 6.6,16.7 v8.5,18.6
  Bottom 0.19: v18.88,21.38 16.75,23.5 9.25,23.5 7.62,21.88 v7.6,21.8
  Bottom 0.2: v7.6,21.8 6.8,21.8 ESDA.X | v33.6,17 30.7,17 v29.8,17.9
PA09_S0_I2C_SCL  (via drill 0.2)
  Top 0.19: v30.25,18.38 30.25,18.4 | v27.12,19.38 27.12,19.25
  Top 0.2: 28.5,16.07 U1.14 28.48,16.02 28.5,16.05 28.5,17.2 28.45,17.25 | 28.45,17.25 29.6,18.4 30.25,18.4 32.25,18.4 R13.1 32.4,17.15 32.71,16.84 U4.6 | v9.3,21 9.5,20.8 J4.3 v9.5,18.6 | U5.5 7.15,8.35 v6.9,8.6 | 27.12,19.25 27.12,18.57 28.45,17.25
  PWR 0.19: v30.25,18.38 29.25,19.38 29.25,19.8 31.07,21.62 32.75,21.62 33.75,22.62 33.75,23 34.5,23.75 38.88,23.75 39.88,22.75 J5.7
  MID 0.19: v27.12,19.38 26.88,19.38 26.75,19.25 25.62,19.25 25.38,19.5 24.55,19.5
  MID 0.2: v6.9,8.6 6.9,14.55 7,14.65 7,16.1 v9.5,18.6 10.35,19.45 22.15,19.45 22.35,19.25 24.3,19.25 24.55,19.5
  Bottom 0.2: v9.3,21 ESCL.X
PA10_TCC0-W2  (via drill 0.2)
  Top 0.2: U1.15 28,16.07 28,16.85 v28.05,16.9
  PWR 0.2: J3.11 47.5,2.38 47.5,4.3 44.9,6.9 44.9,8.5 46.25,9.85 46.25,12.05 v46.2,12.1
  MID 0.2: 47.5,2.38 J3.11 45.7,4.17 45.7,4.7 45.4,5 34.8,5 34.3,5.5 34.3,13.3 32.9,14.7 31.4,16.1 28.85,16.1 v28.05,16.9
  Bottom 0.2: 46.08,12.22 v46.2,12.1 45.95,12.35 44.3,12.35 43.7,11.75 U7.3
PA11_TCC0-W3  (via drill 0.2)
  Top 0.2: v27.4,17.55 27.4,16.07 U1.16
  PWR 0.2: v46.7,12.7 46.7,9.8 45.3,8.4 45.3,7.12 J3.12
  MID 0.19: 46.9,5 47.8,4.1
  MID 0.2: J3.12 49.56,2.34 47.8,4.1 | v27.4,17.55 27.5,17.6 28.1,17.6 29.2,16.5 31.7,16.5 34.7,13.5 34.7,5.7 35,5.4 46.5,5.4 46.9,5
  Bottom 0.2: U7.2 43.3,11.85 44.2,12.75 46.65,12.75 v46.7,12.7
PA12_S2_TX  (via drill 0.2)
  Top 0.2: v24.1,19.7 24.2,19.7 24.7,19.2 24.7,18.7 24.95,18.45 U1.21
  MID 0.19: v42.7,13.95 37.35,13.95 33.4,17.9
  MID 0.2: v24.1,19.7 24.5,20.1 26.2,20.1 26.3,20.2 26.7,20.2 26.8,20.1 30.5,20.1 32.7,17.9 33.4,17.9
  Bottom 0.2: U2.2 43.2,15.45 42.7,14.95 v42.7,13.95
PA13_S2_RX  (via drill 0.2)
  Top 0.2: U1.22 24.45,18.45 v23.2,19.7
  MID 0.19: v43.4,14.45 37.45,14.45 33.6,18.3
  MID 0.2: v23.2,19.7 23.2,20.2 24.2,21.2 30,21.2 32.9,18.3 33.6,18.3
  Bottom 0.2: U2.1 43.6,15.05 43.4,14.85 v43.4,14.45
PA14_S2_RTS  (via drill 0.2)
  Top 0.2: v23.6,18.3 23.9,18 23.9,16.07 U1.23
  Bottom 0.2: v23.6,18.3 24.8,19.5 25.4,19.5 26.9,18 29.2,18 31.2,20 32.8,20 35.6,17.2 42.1,17.2 43.05,16.25 U2.4
PA15_S2_CTS  (via drill 0.2)
  Top 0.19: v23.38,16.75 23.38,16.12 U1.24
  MID 0.19: v23.38,16.75 23.38,9 22.9,8.53 22.9,7.85 24.82,5.92 24.82,5.05 25.5,4.38 v25.5,4.25
  Bottom 0.19: v25.5,4.25 26.25,5 31.1,5 40.73,14.62 41.38,14.62 42.6,15.85 U2.3
PA16_S1_MOSI  (via drill 0.2)
  Top 0.19: v22.75,17 22.75,15.25 U1.25
  PWR 0.19: v43.25,18.25 46.62,21.62 49,21.62 50,22.62 J5.3
  Bottom 0.19: 31,20.38 30.75,20.15 23,20.15 22.75,19.9 v22.75,17 | v43.25,18.25 40.5,18.25
  Bottom 0.2: 31,20.38 33.17,20.38 35.3,18.25 40.5,18.25
PA17_S1_SCK  (via drill 0.2)
  Top 0.19: U1.26 22.3,14.75 22,15.05 22,17.25 22.88,18.12 22.88,18.75 22.05,19.57 19.75,19.57 19.25,20.07 19.25,21.12 v19.5,21.38
  MID 0.19: v19.5,21.38 21.12,23 21.12,23.12 21.88,23.88 46.38,23.88 47.5,22.75 J5.4
PA18_OTG  (via drill 0.2)
  Top 0.19: U1.27 22.3,14.25 21.62,14.93 21.62,15.38 21,16 17,16 14.5,13.5 v8.88,13.5
  Top 0.2: J1.4 5.15,11.85 v5.2,11.9
  Bottom 0.19: v8.88,13.5 7.12,11.75 5.75,11.75 USB_ID.X | 5.12,11.88 v5.2,11.9
  Bottom 0.2: USB_ID.X 5.45,11.9 v5.2,11.9 5.2,12.5 3.45,14.25 R21.2 1.95,13.8 1.6,13.45 1.6,12.77 Q3.G
PA19_S1_MISO  (via drill 0.2)
  Top 0.2: U1.28 21.55,13.75 v21.3,14
  PWR 0.2: v21.3,14 26.55,14 30.7,18.15 30.7,18.6 30.4,18.9 30.4,20.4 31.25,21.27 33.08,21.27 v33.6,21.8
  MID 0.2: v33.6,21.8 33.6,21.6 33.8,21.5 43.84,21.5 J5.5
PA20_TCC0-W6  (via drill 0.2)
  Top 0.2: Q1.G 15.32,22.73 R16.2 15.25,22.65 v14.5,22.65 | 20.8,15.4 v20.8,15.5 21.1,15.2 21.1,14.65 20.85,14.4 20.85,13.6 21.05,13.4 21.6,13.4 21.75,13.25 U1.29
  PWR 0.19: J5.1 55.12,22.75 53.25,24.62 16.5,24.62 14.5,22.62 v14.5,22.65
  Bottom 0.2: v20.8,15.5 20.8,17.25 R16.2 14.6,22.75 v14.5,22.65
PA21_TCC0-W7  (via drill 0.2)
  Top 0.2: J4.2 10.5,20.7 v10.8,21 | U1.30 21.75,12.75 21.5,13 20.9,13 20.5,13.4 20.5,14.7 v20.6,14.8
  MID 0.19: J5.2 52.5,22.75 51,24.25 21.12,24.25 18.12,21.25 11.12,21.25 10.88,21 v10.8,21
  Bottom 0.2: v10.8,21 11.3,21.5 11.58,21.5 EWK.X 12.48,22.4 14,22.4 14.2,22.2 15.2,22.2 20.3,17.1 20.3,15.1 v20.6,14.8
PA22_TC4-W0  (via drill 0.2)
  Top 0.19: U1.31 21.62,12.25 v21.38,12.5
  MID 0.19: v21.38,12.5 20.5,11.62 20.5,2.5 21.75,1.25 41.38,1.25 42.38,2.25 J3.9
PA23_TC4-W1  (via drill 0.2)
  Top 0.19: U1.32 21.5,11.75 v21.38,11.88
  MID 0.19: v21.38,11.88 21.88,12.38 21.88,12.62 21.5,13 21.25,13 20.12,11.88 20.12,2.38 21.62,0.88 43.5,0.88 44.88,2.25 J3.10
PA27_INT  (via drill 0.2)
  Top 0.19: v23.38,6.62 24.5,7.75 24.5,8.88 U1.39
  Top 0.2: v7.7,8.7 7.65,8.75 7.65,9.1 R24.2 | U5.7 5,5.9 4.5,5.4 v3.9,5.4
  Bottom 0.19: v23.38,6.62 21.88,8.12 21.62,8.12 20.62,9.12 | 14.75,23.12 12.12,23.12 10,21 | 7.75,9.12 7.75,8.75 v7.7,8.7
  Bottom 0.2: v7.7,8.7 8.3,8.1 8.3,7.5 8,7.2 6.3,7.2 4.4,5.3 4,5.3 v3.9,5.4 | 20.62,9.12 20.62,14.12 21.25,14.75 21.25,18.15 16.27,23.12 14.75,23.12 | 7.75,9.12 7.75,9.7 7.92,9.88 10.62,9.88 12.05,11.3 12.05,18.15 10,20.2 10,21
PA28_S2_DTR  (via drill 0.2)
  Top 0.19: U1.41 25.45,8.18 v25.55,8.07
  PWR 0.19: v25.55,8.07 25.9,7.72 25.9,7.12 27.02,6 27.73,6 27.75,6.03 28.4,6.03 29,6.62 v30.2,6.62
  Bottom 0.19: v30.2,6.62 31.73,6.62 34.85,9.75 R11.2
PA30_SWCLK  (via drill 0.2)
  Top 0.19: v27,7.5 27.27,7.5 27.45,7.67 U1.45
  Bottom 0.2: v27,7.5 26.8,7.5 26.4,7.9 26.4,13.17 J2.4 24.9,14.77 24.9,16.1 24.6,16.4 R4.1
PA31_SWDIO  (via drill 0.2)
  Top 0.2: U1.46 27.95,7.95 v28,7.95
  Bottom 0.2: J2.2 28.25,13.86 28.25,8.2 v28,7.95
PB02_AIN10
  Top 0.2: U1.47 28.45,3.58 J3.3
PB03_AIN11
  Top 0.2: U1.48 28.95,3.15 J3.4
PB08_RST  (via drill 0.2)
  Top 0.19: v49.5,16 50.25,15.25 50.25,13.25 50,13 47.05,13 44.92,15.12 41.25,15.12 v41.2,15.2
  Top 0.2: U1.7 30.45,12.75 v30.6,12.9
  Bottom 0.19: v49.5,16 50,16 50.12,16.12 Q5.2 | 30.7,13 38.4,13 40.6,15.2 v41.2,15.2
  Bottom 0.2: 30.7,13 v30.6,12.9 | v41.2,15.2 R10.2
PB10_TCC0-W4  (via drill 0.2)
  Top 0.19: 26,16.07 U1.19
  Top 0.2: 26,16.07 26,16.75 v25.85,16.9
  MID 0.19: 33.7,15.1 31.9,16.9 29.4,16.9 28.2,18.1 27.2,18.1 | 49.2,5.4 50.8,3.8
  MID 0.2: J3.13 52.26,2.34 50.8,3.8 | 49.2,5.4 48.7,5.9 35.2,5.9 35.1,6 35.1,13.7 33.7,15.1 | 27.2,18.1 27.05,18.1 v25.85,16.9
PB11_TCC0-W5  (via drill 0.2)
  Top 0.19: v25.4,17.5 25.4,16.07 U1.20
  MID 0.19: J3.14 54.46,2.34 51,5.8 | 34.1,15.2 32.1,17.3 29.6,17.3 28.4,18.5 26.4,18.5 v25.4,17.5
  MID 0.2: 51,5.8 50.5,6.3 35.6,6.3 35.5,6.4 35.5,13.8 34.1,15.2
PB22_S5_TX  (via drill 0.2)
  Top 0.2: U1.37 23.45,8.35 23.4,8.3 v23.4,8
  PWR 0.19: 32.1,9.2 30.1,9.2 29.8,9.5 23.98,9.5 U1.37 23.45,8.05 v23.4,8
  PWR 0.2: 34.8,22.62 J5.9 34.7,22.52 34.7,20.8 32.7,18.8 32.7,9.8 32.1,9.2
PB23_S5_RX  (via drill 0.2)
  Top 0.2: U1.38 23.95,8.05 v24,8
  PWR 0.19: 32.3,8.8 29.9,8.8 29.57,9.12 24.12,9.12 24,9 v24,8
  PWR 0.2: 32.3,8.8 33.1,9.6 33.1,18.39 J5.8
RESET#
  Top 0.2: 32.34,22.62 32.34,21.55 R6.2
  Top 0.305: 32.34,22.62 J5.10
RESETN  (via drill 0.2)
  Top 0.2: R6.1 R3.2 C2.1 v29.7,19.6 R5.1 | U1.40 24.95,7.75 v25.35,7.35
  MID 0.2: v29.7,19.6 29,18.9 26.1,18.9 24.9,17.7 24.9,7.8 v25.35,7.35
  Bottom 0.2: R2.2 26.1,7.1 25.6,7.1 v25.35,7.35
SCLK  (via drill 0.2)
  Top 0.2: U3.38 v41.8,4.5
  MID 0.19: 54.1,12.7 v54.3,12.9
  MID 0.2: v45.8,8.2 49.4,11.8 52,11.8 52.9,12.7 54.1,12.7
  Bottom 0.19: v54.3,12.9 53.6,12.9 SIM1.CLK
  Bottom 0.2: v41.8,4.5 41.8,5.4 43.5,7.1 44.7,7.1 v45.8,8.2 | 53.46,12.9 SIM1.CLK 53.71,12.95 53.15,12.95 52.55,13.55 D5.2
SIO  (via drill 0.2)
  Top 0.19: U3.39 v42.9,4.5
  MID 0.2: v46.6,8.3 49.7,11.4 52.2,11.4 53.1,12.3 54.4,12.3 54.8,12.7 54.8,13.6 v54.3,14.1
  Bottom 0.19: 45,6.7 v46.6,8.3 | v54.3,14.1 53.56,14.1 SIM1.IO
  Bottom 0.2: v42.9,4.5 42.9,5.9 43.7,6.7 45,6.7 | 53.5,14.1 SIM1.IO 53.71,14.05 53.1,14.05 52.6,14.55 D6.2
SRST  (via drill 0.2)
  Top 0.2: U3.40 v44,4.5
  MID 0.2: v46.7,7.7 49.8,10.8 v54.2,10.8
  Bottom 0.19: 44,6.1 44.2,6.3 45.3,6.3 | v54.2,10.8 53.56,10.8 SIM1.RST
  Bottom 0.2: v44,4.5 44,6.1 | 45.3,6.3 v46.7,7.7 | 53.51,10.75 SIM1.RST 53.7,10.8 53.2,10.8 52.75,11.25 52.75,12.35 52.55,12.55 D4.2
SSW
  Bottom 0.2: Q5.5 52.5,16.15 52.8,15.85 54.35,15.85 54.85,15.35 54.85,10 54.52,9.67 SIM1.SW 52.62,9.67 R31.1
STAT  (via drill 0.2)
  Top 0.305: U5.4 7.65,7.65 v7.7,7.7 | 3,6.1 DL2.C 3,6 v4.2,6
  Bottom 0.305: v7.7,7.7 5.9,7.7 v4.2,6
SVCC  (via drill 0.2)
  Top 0.305: U3.41 v45.1,4.5
  PWR 0.305: v46.7,7 49.2,9.5 52.85,9.5 v54.85,7.5
  Bottom 0.305: v45.1,4.5 45.1,5.8 45.2,5.9 45.6,5.9 v46.7,7 | 53.6,7.4 SIM1.VCC | 53.65,7.35 SIM1.VCC | C32.2 52.6,5.55 53.5,6.45 53.5,7.44 SIM1.VCC | SIM1.VCC 54.82,7.47 v54.85,7.5
USB_N  (via drill 0.2)
  Top 0.19: J1.2 arc90 4.29,12.98 7.9,12.98 | U1.33 21.58,11.25 arc-90 20.93,11.9 20.93,11.85 arc90 19.8,12.98 7.9,12.98 | 7.9,12.98 8,13.08 8,13.8
  Top 0.24: v8,14.7 D1.3 D-.X 8,13.8
  Bottom 0.19: D-.X 8.2,14 9.22,14 R17.1
  Bottom 0.24: v8,14.7 8,14.1 D-.X
USB_P  (via drill 0.2)
  Top 0.19: J1.3 arc-90 4.24,12.62 7.9,12.62 | U1.34 21.72,10.75 arc-90 20.57,11.8 20.57,11.85 arc90 19.8,12.62 7.9,12.62 | D1.2 8,12.52 7.9,12.62
  Top 0.24: D1.2 v8,10.9
  Bottom 0.2: D+.X 9.15,12.65 R7.1
  Bottom 0.24: 8,11.5 D+.X 8,11.6 v8,10.9
V_BCKP  (via drill 0.2)
  Top 0.19: v57.75,20.5 57.12,19.88 57.12,19.5 U3.2
  Bottom 0.19: v57.75,20.5 57.25,20
  Bottom 0.2: 57.25,20 R12.2
VBATT  (via drill 0.2)
  Top 0.305: U5.14 U5.13
  Top 0.61: U5.13 v6.5,2.5 | v14.1,10.1 14.1,11.25 D2.C 12.2,11.3 F2.2
  PWR 0.2: v6.5,2.5 U5.13 6.8,2.65 9.45,2.65 9.9,3.1 14.4,3.1 v15.8,1.7
  Bottom 0.2: R8.2 29.4,7.1 27.7,5.4 19.5,5.4 v15.8,1.7
  Bottom 0.61: v6.5,2.5 8.85,2.5 9.88,3.5 13,3.5 14.1,4.6 BATT+.X v14.1,10.1
VIN  (via drill 0.2)
  Top 0.2: Q2.A 10.65,11.1 | R19.2 10.65,11.1 | 10.65,11.1 v10.6,11.15 | Q2.G 10,7.7 v10.1,7.6
  PWR 0.2: v10.1,7.6 10.1,10.65 v10.6,11.15
  PWR 0.61: v10.6,11.15 10.6,18 12.2,19.6 21.61,19.6 J5.13 24.7,22.64
VUSB1  (via drill 0.2)
  Top 0.305: U5.23 10.5,5.4 10.8,5.7 v11,5.7
  Top 0.61: v13.9,21.7 D3.A | v12.7,14.4 12.6,14.3 C12.1 11.2,15.2 C13.1
  Bottom 0.61: v11,5.7 12.2,5.7 12.7,6.2 v12.7,14.4 12.7,20.5 v13.9,21.7

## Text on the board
Reference: Arturo Guadalupi
test-probe: 5V | VIN(5V) | VCC | GND | RESET | 14 | 13 | 12 | 11 | 10 | 9 | 8 | 7 | 6 | USB_5V | USB_D- | SWCLK | SWDIO | JGND | JRST | VTG | BATT+ | BATT- | USB_D+ | USB_GND | AREF | A0 | A1 | A2 | A3 | A4 | A5 | A6 | 0 | 1 | 2 | 3 | 4 | 5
